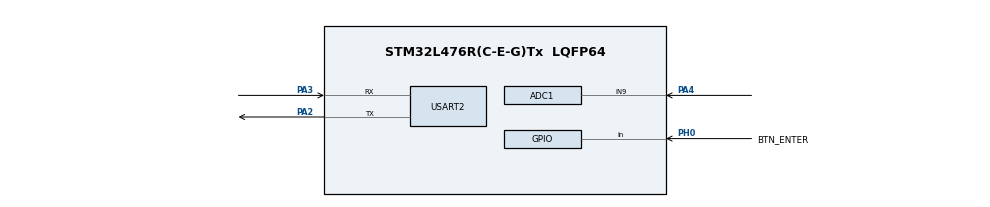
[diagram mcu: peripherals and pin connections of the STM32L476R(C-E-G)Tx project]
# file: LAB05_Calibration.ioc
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ADC1.Channel-0\#ChannelRegularConversion=ADC_CHANNEL_9
ADC1.NbrOfConversionFlag=1
ADC1.OffsetNumber-0\#ChannelRegularConversion=ADC_OFFSET_NONE
ADC1.Rank-0\#ChannelRegularConversion=1
ADC1.SamplingTime-0\#ChannelRegularConversion=ADC_SAMPLETIME_12CYCLES_5
ADC1.master=1
Mcu.Family=STM32L4
Mcu.Name=STM32L476R(C-E-G)Tx
Mcu.Package=LQFP64
NVIC.PriorityGroup=NVIC_PRIORITYGROUP_4
PA2.Mode=Asynchronous
PA2.Signal=USART2_TX
PA3.Mode=Asynchronous
PA3.Signal=USART2_RX
PA4.Signal=ADCx_IN9
PH0-OSC_IN\ (PH0).GPIO_Label=BTN_ENTER
PH0-OSC_IN\ (PH0).Signal=GPIO_Input
ProjectManager.HeapSize=0x200
ProjectManager.StackSize=0x400
ProjectManager.TargetToolchain=STM32CubeIDE
RCC.ADCFreq_Value=32000000
RCC.AHBFreq_Value=80000000
RCC.APB1Freq_Value=80000000
RCC.APB1TimFreq_Value=80000000
RCC.APB2Freq_Value=80000000
RCC.APB2TimFreq_Value=80000000
RCC.CortexFreq_Value=80000000
RCC.HCLKFreq_Value=80000000
RCC.HSE_VALUE=8000000
RCC.HSI_VALUE=16000000
RCC.LSE_VALUE=32768
RCC.MSI_VALUE=4000000
RCC.PLLN=40
RCC.PLLSAI1N=16
RCC.SYSCLKFreq_VALUE=80000000
RCC.SYSCLKSource=RCC_SYSCLKSOURCE_PLLCLK
RCC.USBFreq_Value=32000000
RCC.VCOOutputFreq_Value=160000000
SH.ADCx_IN9.0=ADC1_IN9,IN9-Single-Ended
USART2.VirtualMode-Asynchronous=VM_ASYNC
VP_ADC1_Vref_Input.Mode=IN-Vrefint
board=custom

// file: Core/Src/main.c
/* USER CODE BEGIN Header */
/**
 * @file main.c
 * @brief ADC Calibration Exercise.
 * @author Philipp Schilk, 2023
 */
/* USER CODE END Header */
#include "main.h"

/* USER CODE BEGIN Includes */
#include <inttypes.h>
#include <stdio.h>
/* USER CODE END Includes */

/* USER CODE BEGIN PM */
#define TODO 0
/* USER CODE END PM */

ADC_HandleTypeDef hadc1;

UART_HandleTypeDef huart2;

void SystemClock_Config(void);
static void MX_GPIO_Init(void);
static void MX_ADC1_Init(void);
static void MX_USART2_UART_Init(void);
/* USER CODE BEGIN PFP */
static HAL_StatusTypeDef ReadADC(uint32_t *result, uint32_t readings_to_average);
static void wait_for_button_press(void);
/* USER CODE END PFP */

int main(void) {

  /* MCU Configuration--------------------------------------------------------*/

  /* Reset of all peripherals, Initializes the Flash interface and the Systick. */
  HAL_Init();

  /* Configure the system clock */
  SystemClock_Config();

  /* Initialize all configured peripherals */
  MX_GPIO_Init();
  MX_ADC1_Init();
  MX_USART2_UART_Init();
  /* USER CODE BEGIN 2 */

  // ====== STEP 1: Determining VREFINT =======

  // First we will use the internal calibration register to determine
  // the voltage of the internal voltage reference.

  // TODO: Create a pointer to the calibration register:
  volatile uint16_t *VREFINT_CAL = (volatile uint16_t *)0x1FFF75AA;

  // TODO: Calculate the voltage of the internal reference based on
  //       the calibration register value and the Vdda voltage with which
  //       this calibration register was measured at the factory.
  float vrefint_voltage_calibrated = (float)*VREFINT_CAL / 4095.0 * 3.0;

  // ====== STEP 2: Calibrating the ADC =======

  // TODO: Run the ADC self-calibration routine. If it fails, print
  //       an error message and call Error_Handler().
  if (HAL_ADCEx_Calibration_Start(&hadc1, ADC_SINGLE_ENDED) != HAL_OK) {
    printf("ERROR occurred during calibration\r\n");
    Error_Handler();
  }

  // Wait for the calibration to complete:
  HAL_Delay(100);

  /* USER CODE END 2 */

  /* Infinite loop */
  /* USER CODE BEGIN WHILE */
  while (1) {

    // ====== STEP 4: ADC Channel Switching =======

    ADC_ChannelConfTypeDef sConfig = {0};

    uint32_t vrefint_raw_reading = 0;
    uint32_t poti_raw_reading = 0;

    // TODO: Configure ADC! to measure the Vrefint channel.
    //       If the HAL function fails, print an error message and call Error_Handler().
    // HINT: Use the MX_ADC1_Init() function generated by CubeMX as refernce.
    sConfig.Channel = ADC_CHANNEL_VREFINT; // since I cant access init sConfig, imma just have to copy settings here
    sConfig.Rank = ADC_REGULAR_RANK_1;
    sConfig.SamplingTime = ADC_SAMPLETIME_247CYCLES_5;
    sConfig.SingleDiff = ADC_SINGLE_ENDED;
    sConfig.OffsetNumber = ADC_OFFSET_NONE;
    sConfig.Offset = 0;

    if (HAL_ADC_ConfigChannel(&hadc1, &sConfig) != HAL_OK) {
      printf("ERROR HAL ADC config\r\n");
      Error_Handler();
    }

    // Read the VREFINT channel 20 times and average the result:
    if (ReadADC(&vrefint_raw_reading, 20) != HAL_OK) {
      printf("ReadADC failed!\r\n");
      Error_Handler();
    }

    // TODO: Configure the ADC1 to measure the potentiometer channel.
    //       If the HAL function fails, print an error message and call Error_Handler().
    sConfig.SamplingTime = ADC_SAMPLETIME_12CYCLES_5;
    sConfig.Channel = ADC_CHANNEL_9;

    if (HAL_ADC_ConfigChannel(&hadc1, &sConfig) != HAL_OK) {
      printf("ERROR HAL ADC config\r\n");
      Error_Handler();
    }
    // Read the poti channel 20 times and average the result:
    if (ReadADC(&poti_raw_reading, 20) != HAL_OK) {
      printf("ReadADC failed!\r\n");
      Error_Handler();
    }

    // ====== STEP 5: Calculations =======

    // TODO: Convert the potentiometer ADC reading to a voltage assuming Vdda = 3.3V:
    // NOTE: This is the "un-calibrated" result, which we will use as a point of comparison.
    float poti_voltage_uncalibrated = (float)poti_raw_reading / 4095.0 * 3.3;

    // TODO: Use your Vrefint measurement and calculated Vrefint voltage to determine the actual
    //       Vdda voltage of your specific board:
    float vdda_voltage_calibrated = 3.0 * ((float)*VREFINT_CAL / (float)vrefint_raw_reading);

    // TODO: Convert the potentiometer ADC reading to a voltage, using your measured voltage for
    //       Vdda:
    float poti_voltage_calibrated = (float)poti_raw_reading / 4095.0 * vdda_voltage_calibrated;

    // Print results:
    printf("\r\n\r\n\r\n");

    printf("\r\nStep 1:\r\n");
    // VREFINT calibration register value:
    printf("Vrefint calibration register:  %8" PRIu32 " LSBs\r\n", *VREFINT_CAL);
    // Vrefint expected voltage according to datasheet:
    printf("Vrefint assumed voltage:       %.6f    V\r\n", 1.212);
    // Vrefint actual voltage as determined by factory calibration:
    printf("Vrefint calibrated voltage:    %.6f    V\r\n", vrefint_voltage_calibrated);

    printf("\r\nStep 2:\r\n");
    // Raw ADC reading of the Vrefint reference:
    printf("Vrefint reading:               %8" PRIu32 " LSBs\r\n", vrefint_raw_reading);
    // Raw poti reading:
    printf("POTI reading:                  %8" PRIu32 " LSBs\r\n", poti_raw_reading);

    printf("\r\nStep 3:\r\n");
    // Vdda (ADC full-scale voltage) as specified in the nucleo board schematic:
    printf("Vdda assumed voltage:          %.6f    V\r\n", 3.3);
    // Actual Vdda, as measured using Vrefint:
    printf("Vdda calibrated voltage:       %.6f    V\r\n", vdda_voltage_calibrated);
    // Poti reading converted to voltage assuming Vdda = 3.3V
    printf("POTI uncalibrated voltage:     %.6f    V\r\n", poti_voltage_uncalibrated);
    // Poti reading converted to voltage using measured Vdda
    printf("POTI calibrated voltage:       %.6f    V\r\n", poti_voltage_calibrated);

    printf("Press ENTER to re-measure...\r\n");
    wait_for_button_press();
    /* USER CODE END WHILE */

  }
}

void SystemClock_Config(void) {
  RCC_OscInitTypeDef RCC_OscInitStruct = {0};
  RCC_ClkInitTypeDef RCC_ClkInitStruct = {0};

  /** Configure the main internal regulator output voltage
   */
  if (HAL_PWREx_ControlVoltageScaling(PWR_REGULATOR_VOLTAGE_SCALE1) != HAL_OK) {
    Error_Handler();
  }

  /** Initializes the RCC Oscillators according to the specified parameters
   * in the RCC_OscInitTypeDef structure.
   */
  RCC_OscInitStruct.OscillatorType = RCC_OSCILLATORTYPE_MSI;
  RCC_OscInitStruct.MSIState = RCC_MSI_ON;
  RCC_OscInitStruct.MSICalibrationValue = 0;
  RCC_OscInitStruct.MSIClockRange = RCC_MSIRANGE_6;
  RCC_OscInitStruct.PLL.PLLState = RCC_PLL_NONE;
  if (HAL_RCC_OscConfig(&RCC_OscInitStruct) != HAL_OK) {
    Error_Handler();
  }

  /** Initializes the CPU, AHB and APB buses clocks
   */
  RCC_ClkInitStruct.ClockType = RCC_CLOCKTYPE_HCLK | RCC_CLOCKTYPE_SYSCLK | RCC_CLOCKTYPE_PCLK1 | RCC_CLOCKTYPE_PCLK2;
  RCC_ClkInitStruct.SYSCLKSource = RCC_SYSCLKSOURCE_MSI;
  RCC_ClkInitStruct.AHBCLKDivider = RCC_SYSCLK_DIV1;
  RCC_ClkInitStruct.APB1CLKDivider = RCC_HCLK_DIV1;
  RCC_ClkInitStruct.APB2CLKDivider = RCC_HCLK_DIV1;

  if (HAL_RCC_ClockConfig(&RCC_ClkInitStruct, FLASH_LATENCY_0) != HAL_OK) {
    Error_Handler();
  }
}

static void MX_ADC1_Init(void) {

  ADC_MultiModeTypeDef multimode = {0};
  ADC_ChannelConfTypeDef sConfig = {0};

  /** Common config
   */
  hadc1.Instance = ADC1;
  hadc1.Init.ClockPrescaler = ADC_CLOCK_ASYNC_DIV1;
  hadc1.Init.Resolution = ADC_RESOLUTION_12B;
  hadc1.Init.DataAlign = ADC_DATAALIGN_RIGHT;
  hadc1.Init.ScanConvMode = ADC_SCAN_DISABLE;
  hadc1.Init.EOCSelection = ADC_EOC_SINGLE_CONV;
  hadc1.Init.LowPowerAutoWait = DISABLE;
  hadc1.Init.ContinuousConvMode = DISABLE;
  hadc1.Init.NbrOfConversion = 1;
  hadc1.Init.DiscontinuousConvMode = DISABLE;
  hadc1.Init.ExternalTrigConv = ADC_SOFTWARE_START;
  hadc1.Init.ExternalTrigConvEdge = ADC_EXTERNALTRIGCONVEDGE_NONE;
  hadc1.Init.DMAContinuousRequests = DISABLE;
  hadc1.Init.Overrun = ADC_OVR_DATA_PRESERVED;
  hadc1.Init.OversamplingMode = DISABLE;
  if (HAL_ADC_Init(&hadc1) != HAL_OK) {
    Error_Handler();
  }

  /** Configure the ADC multi-mode
   */
  multimode.Mode = ADC_MODE_INDEPENDENT;
  if (HAL_ADCEx_MultiModeConfigChannel(&hadc1, &multimode) != HAL_OK) {
    Error_Handler();
  }

  /** Configure Regular Channel
   */
  sConfig.Channel = ADC_CHANNEL_9;
  sConfig.Rank = ADC_REGULAR_RANK_1;
  sConfig.SamplingTime = ADC_SAMPLETIME_12CYCLES_5;
  sConfig.SingleDiff = ADC_SINGLE_ENDED;
  sConfig.OffsetNumber = ADC_OFFSET_NONE;
  sConfig.Offset = 0;
  if (HAL_ADC_ConfigChannel(&hadc1, &sConfig) != HAL_OK) {
    Error_Handler();
  }
}

static void MX_USART2_UART_Init(void) {

  huart2.Instance = USART2;
  huart2.Init.BaudRate = 115200;
  huart2.Init.WordLength = UART_WORDLENGTH_8B;
  huart2.Init.StopBits = UART_STOPBITS_1;
  huart2.Init.Parity = UART_PARITY_NONE;
  huart2.Init.Mode = UART_MODE_TX_RX;
  huart2.Init.HwFlowCtl = UART_HWCONTROL_NONE;
  huart2.Init.OverSampling = UART_OVERSAMPLING_16;
  huart2.Init.OneBitSampling = UART_ONE_BIT_SAMPLE_DISABLE;
  huart2.AdvancedInit.AdvFeatureInit = UART_ADVFEATURE_NO_INIT;
  if (HAL_UART_Init(&huart2) != HAL_OK) {
    Error_Handler();
  }
}

static void MX_GPIO_Init(void) {
  GPIO_InitTypeDef GPIO_InitStruct = {0};

  /* GPIO Ports Clock Enable */
  __HAL_RCC_GPIOH_CLK_ENABLE();
  __HAL_RCC_GPIOA_CLK_ENABLE();

  /*Configure GPIO pin : BTN_ENTER_Pin */
  GPIO_InitStruct.Pin = BTN_ENTER_Pin;
  GPIO_InitStruct.Mode = GPIO_MODE_INPUT;
  GPIO_InitStruct.Pull = GPIO_NOPULL;
  HAL_GPIO_Init(BTN_ENTER_GPIO_Port, &GPIO_InitStruct);

}

/* USER CODE BEGIN 4 */

/**
 * @brief Read ADC multiple times and return the average reading
 *
 * @param result pointer to variable where the average of the readings should be stored
 * @param readings_to_average number of ADC readings to perform and average.
 * @return HAL_OK if successful, otherwise the error code returned by the failing HAL function.
 */
static HAL_StatusTypeDef ReadADC(uint32_t *result, uint32_t readings_to_average) {

  // ====== STEP 3: ADC Measurements =======

  HAL_StatusTypeDef err = HAL_OK;

  // Prevent a division-by-zero:
  if (readings_to_average == 0) {
    return HAL_ERROR;
  }

  // Sum of all readings:
  uint64_t sum = 0;

  for (size_t i = 0; i < readings_to_average; i++) {
    // TODO: Start ADC conversion. If it fails, print an error message and
    //       return the error code it returned.
    if (HAL_ADC_Start(&hadc1) != HAL_OK) {
      printf("ERROR starting ADC conversion (iteration [%i/%" PRIu32 "]\r\n", i, readings_to_average);
      return HAL_ERROR;
    }

    // TODO: Wait for ADC conversion to finish. If it fails,
    //       print an error message and return the error code it returned.
    if (HAL_ADC_PollForConversion(&hadc1, 20) != HAL_OK) {
      printf("ERROR polling ADC\r\n");
      return HAL_ERROR;
    }

    // TODO Retrieve the conversion result and add it to the sum:
    sum += HAL_ADC_GetValue(&hadc1);
    ;
  }

  // TODO: Calculate the average of all readings:
  *result = (float)sum / (float)readings_to_average;

  // Return OK:
  return HAL_OK;
}

static void wait_for_button_press(void) {
  // If the button is already pressed, wait for button to be released:
  while (HAL_GPIO_ReadPin(BTN_ENTER_GPIO_Port, BTN_ENTER_Pin) == GPIO_PIN_RESET) {
  }
  // Wait for the button to be released:
  while (HAL_GPIO_ReadPin(BTN_ENTER_GPIO_Port, BTN_ENTER_Pin) == GPIO_PIN_SET) {
  }
}

/* USER CODE END 4 */

void Error_Handler(void) {
  /* USER CODE BEGIN Error_Handler_Debug */
  /* User can add his own implementation to report the HAL error return state */
  while (1) {
    printf("Stuck in error handler :(\r\n");
    HAL_Delay(4000);
  }
  /* USER CODE END Error_Handler_Debug */
}
